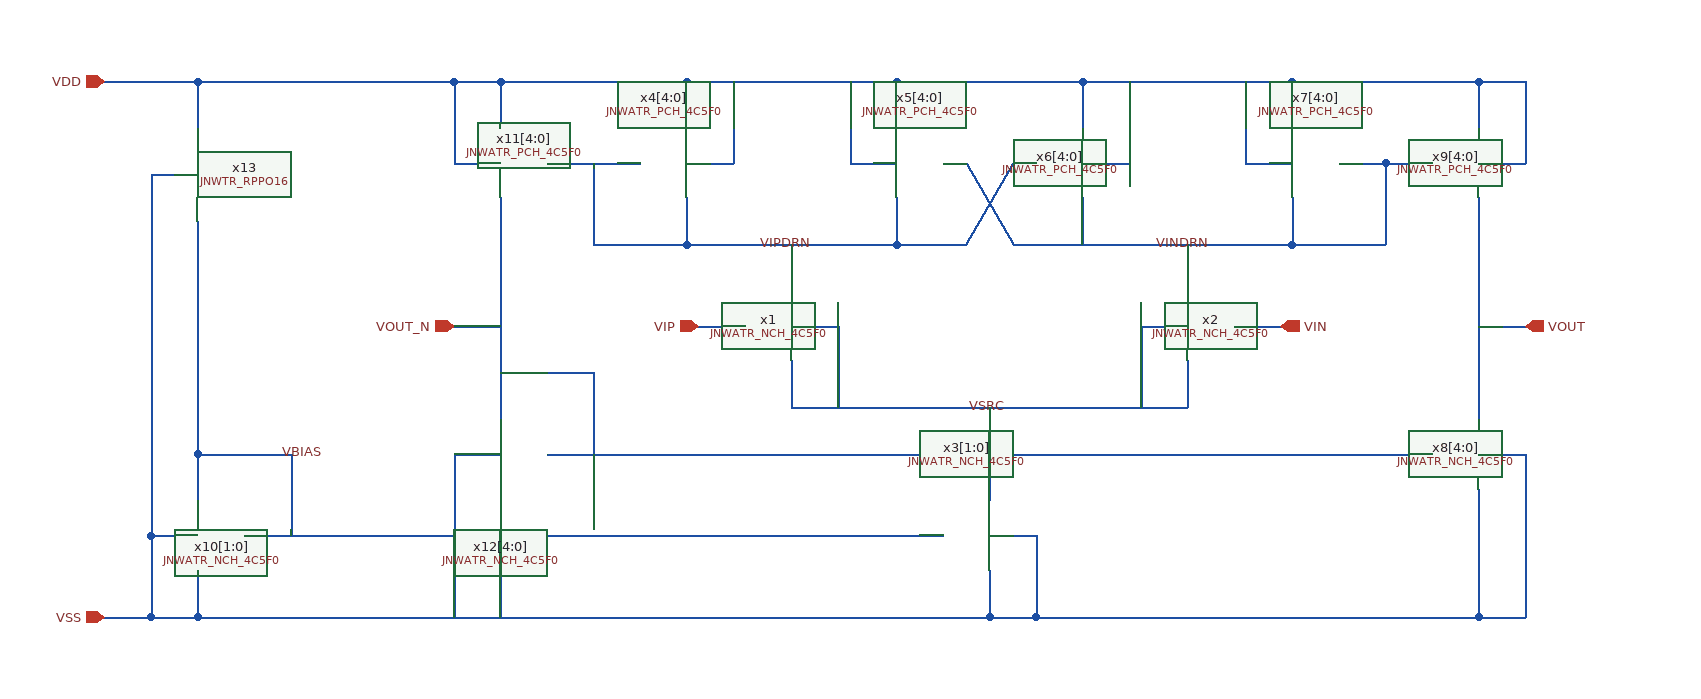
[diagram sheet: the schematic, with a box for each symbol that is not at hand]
v {xschem version=3.4.6 file_version=1.2}
G {}
K {}
V {}
S {}
E {}
N 480 300 520 300 {lab=VDD}
N 480 760 520 760 {lab=VSS}
N 1660 510 1700 510 {lab=VOUT}
N 560 420 560 620 {lab=VBIAS}
N 520 380 540 380 {lab=VSS}
N 520 300 560 300 {lab=VDD}
N 560 300 560 340 {lab=VDD}
N 520 690 560 690 {lab=VSS}
N 560 720 560 760 {lab=VSS}
N 520 760 560 760 {lab=VSS}
N 600 690 1200 690 {lab=VBIAS}
N 560 760 1240 760 {lab=VSS}
N 1240 720 1240 760 {lab=VSS}
N 1070 540 1070 580 {lab=VSRC}
N 1070 580 1410 580 {lab=VSRC}
N 1410 540 1410 580 {lab=VSRC}
N 1240 580 1240 660 {lab=VSRC}
N 1070 510 1110 510 {lab=VSRC}
N 1110 510 1110 580 {lab=VSRC}
N 1370 510 1410 510 {lab=VSRC}
N 1370 510 1370 580 {lab=VSRC}
N 1240 690 1280 690 {lab=VSS}
N 1280 690 1280 760 {lab=VSS}
N 1240 760 1280 760 {lab=VSS}
N 1160 400 1160 440 {lab=VIPDRN}
N 1410 440 1410 480 {lab=VINDRN}
N 1450 510 1490 510 {lab=VIN}
N 990 510 1030 510 {lab=VIP}
N 1220 370 1260 440 {lab=VINDRN}
N 1320 370 1360 370 {lab=VDD}
N 1360 300 1360 370 {lab=VDD}
N 980 370 1020 370 {lab=VDD}
N 1020 300 1020 370 {lab=VDD}
N 1160 300 1160 340 {lab=VDD}
N 1320 300 1320 340 {lab=VDD}
N 520 690 520 760 {lab=VSS}
N 520 380 520 690 {lab=VSS}
N 1000 440 1160 440 {lab=VIPDRN}
N 1220 440 1260 370 {lab=VIPDRN}
N 560 620 640 620 {lab=VBIAS}
N 640 620 640 690 {lab=VBIAS}
N 560 620 560 660 {lab=VBIAS}
N 1660 400 1660 590 {lab=VOUT}
N 1660 650 1660 760 {lab=VSS}
N 1280 760 1660 760 {lab=VSS}
N 1660 300 1660 340 {lab=VDD}
N 1660 370 1700 370 {lab=VDD}
N 1700 300 1700 370 {lab=VDD}
N 1660 300 1700 300 {lab=VDD}
N 1660 620 1700 620 {lab=VSS}
N 1700 620 1700 760 {lab=VSS}
N 1660 760 1700 760 {lab=VSS}
N 1200 370 1220 370 {lab=VINDRN}
N 1260 370 1280 370 {lab=VIPDRN}
N 1260 440 1480 440 {lab=VINDRN}
N 860 620 1620 620 {lab=VOUT_N}
N 780 510 820 510 {lab=VOUT_N}
N 820 400 820 590 {lab=VOUT_N}
N 820 650 820 760 {lab=VSS}
N 820 300 820 340 {lab=VDD}
N 780 370 820 370 {lab=VDD}
N 780 300 780 370 {lab=VDD}
N 780 300 820 300 {lab=VDD}
N 780 620 820 620 {lab=VSS}
N 780 620 780 760 {lab=VSS}
N 1070 440 1070 480 {lab=VIPDRN}
N 980 440 1000 440 {lab=VIPDRN}
N 1480 440 1500 440 {lab=VINDRN}
N 1320 400 1320 440 {lab=VINDRN}
N 1500 300 1500 340 {lab=VDD}
N 1500 400 1500 440 {lab=VINDRN}
N 980 400 980 440 {lab=VIPDRN}
N 980 300 980 340 {lab=VDD}
N 900 440 980 440 {lab=VIPDRN}
N 900 370 900 440 {lab=VIPDRN}
N 860 370 940 370 {lab=VIPDRN}
N 1500 440 1580 440 {lab=VINDRN}
N 1580 370 1580 440 {lab=VINDRN}
N 1580 370 1620 370 {lab=VINDRN}
N 1540 370 1580 370 {lab=VINDRN}
N 1160 440 1220 440 {lab=VIPDRN}
N 820 300 980 300 {lab=VDD}
N 980 300 1070 300 {lab=VDD}
N 1070 300 1160 300 {lab=VDD}
N 1160 300 1320 300 {lab=VDD}
N 1320 300 1410 300 {lab=VDD}
N 1410 300 1500 300 {lab=VDD}
N 1500 300 1660 300 {lab=VDD}
N 560 300 780 300 {lab=VDD}
N 1460 370 1500 370 {lab=VDD}
N 1460 300 1460 370 {lab=VDD}
N 1120 370 1160 370 {lab=VDD}
N 1120 300 1120 370 {lab=VDD}
N 900 550 900 620 {lab=VOUT_N}
N 820 550 900 550 {lab=VOUT_N}
C {devices/ipin.sym} 480 300 0 0 {name=p3 lab=VDD}
C {devices/ipin.sym} 480 760 0 0 {name=p4 lab=VSS}
C {devices/opin.sym} 1700 510 0 0 {name=p5 lab=VOUT
}
C {JNW_TR_SKY130A/JNWTR_RPPO16.sym} 560 340 1 0 {name=x13}
C {JNW_ATR_SKY130A/JNWATR_NCH_4C5F0.sym} 1450 510 0 1 {name=x2}
C {JNW_ATR_SKY130A/JNWATR_NCH_4C5F0.sym} 1200 690 0 0 {name=x3[1:0]}
C {JNW_ATR_SKY130A/JNWATR_NCH_4C5F0.sym} 1030 510 0 0 {name=x1}
C {JNW_ATR_SKY130A/JNWATR_NCH_4C5F0.sym} 600 690 0 1 {name=x10[1:0]}
C {devices/ipin.sym} 1490 510 0 1 {name=p1 lab=VIN}
C {devices/ipin.sym} 990 510 0 0 {name=p2 lab=VIP}
C {JNW_ATR_SKY130A/JNWATR_PCH_4C5F0.sym} 1200 370 0 1 {name=x5[4:0]
}
C {JNW_ATR_SKY130A/JNWATR_PCH_4C5F0.sym} 1280 370 0 0 {name=x6[4:0]
}
C {JNW_ATR_SKY130A/JNWATR_PCH_4C5F0.sym} 1540 370 0 1 {name=x7[4:0]}
C {JNW_ATR_SKY130A/JNWATR_NCH_4C5F0.sym} 1620 620 0 0 {name=x8[4:0]}
C {devices/opin.sym} 780 510 0 1 {name=p6 lab=VOUT_N
}
C {JNW_ATR_SKY130A/JNWATR_PCH_4C5F0.sym} 860 370 0 1 {name=x11[4:0]}
C {JNW_ATR_SKY130A/JNWATR_NCH_4C5F0.sym} 860 620 0 1 {name=x12[4:0]}
C {JNW_ATR_SKY130A/JNWATR_PCH_4C5F0.sym} 940 370 0 0 {name=x4[4:0]
}
C {JNW_ATR_SKY130A/JNWATR_PCH_4C5F0.sym} 1620 370 0 0 {name=x9[4:0]
}
C {devices/lab_wire.sym} 630 620 0 1 {name=p7 sig_type=std_logic lab=VBIAS}
C {devices/lab_wire.sym} 1220 580 0 1 {name=p8 sig_type=std_logic lab=VSRC}
C {devices/lab_wire.sym} 1040 440 0 1 {name=p9 sig_type=std_logic lab=VIPDRN}
C {devices/lab_wire.sym} 1380 440 0 1 {name=p10 sig_type=std_logic lab=VINDRN}
